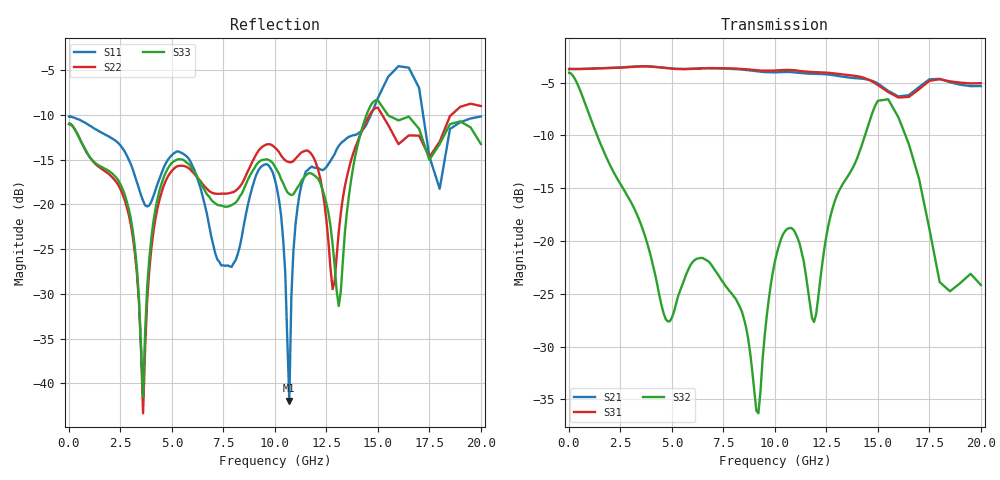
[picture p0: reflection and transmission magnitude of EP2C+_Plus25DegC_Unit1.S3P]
! Mini-Circuits
! S3P DATA File Format
! Type: 2 Way 0 degree Power Splitter
! Model: EP2C+
! Wafer / Lot / Date Code: BH102P002-02/03 / BH102P002-02/03-01EV / 1432
! AUTO PORT EXTENSION DONE: PORT<1>=128.60ps; PORT<2>=85.81ps; PORT<3>=85.38ps
! Network Analyzer: PNA-X N5242A - 423 4 ports;  Serial number: 71256
! PINOUT: SUMPORT=PORT1 , OUT1 PORT=PORT2 , OUT2 PORT=PORT3
! TEST CONDITIONS: INPUT POWER = -10 dBm @ Temperature = + 25 deg C
! S/N: Unit# 1
! Date: 09-Sep-2014
! All S Parameters are in dB deg format
# MHz S DB R 50
!Frequency  S11 dB  S11 DEG  S12 dB  S12 DEG  S13 dB  S13 DEG
!  S21 dB  S21 DEG  S22 dB  S22 DEG  S23 dB  S23 DEG
!  S31 dB  S31 DEG  S32 dB  S32 DEG  S33 dB  S33 DEG
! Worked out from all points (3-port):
!   169 points, 10 MHz to 20 GHz, reference 50 ohm
!   strongest paths, dB at 10 MHz, 3.4 GHz, 7.6 GHz, 11.8 GHz, 20 GHz:
!     S21: -3.7, -3.5, -3.7, -4.2, -5.3
!     S31: -3.7, -3.5, -3.6, -4.0, -5.1
!     S32: -4.1, -17.9, -24.3, -27.3, -24.2
!   lowest |S11| = -41.9 dB at 10.7 GHz (marker M1), VSWR 1.02, Z = 49.4 + j0.55 ohm
!   |S11| at or under -10 dB: start of sweep to 14.66 GHz; 17.2 GHz to end of sweep
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10  -10.18 179.9  -3.73 -0.7  -3.72 -0.3
    -3.73 -0.7  -11.02 178.5  -4.08 -0.7
    -3.72 -0.2  -4.07 -0.5  -11.01 177.9
3600  -19.59 50.8  -3.45 -142.0  -3.48 -143.8
      -3.45 -142.0  -43.33 -157.1  -18.98 -158.0
      -3.48 -143.7  -18.99 -158.0  -41.49 28.9
4500  -16.49 83.3  -3.57 -179.4  -3.59 178.4
      -3.57 -179.4  -18.63 86.4  -26.12 126.8
      -3.59 178.4  -26.13 126.8  -17.66 77.6
6700  -21.05 -8.6  -3.64 89.7  -3.65 86.7
      -3.65 89.7  -18.25 48.4  -21.85 -75.0
      -3.64 86.7  -21.85 -75.0  -18.88 51.9
10100  -18.23 14.3  -4.03 -62.3  -3.86 -66.8
       -4.03 -62.3  -13.88 81.3  -21.11 -57.0
       -3.86 -66.7  -21.13 -57.0  -16.14 68.3
10700  -41.94 135.9  -4.01 -90.7  -3.81 -95.9
       -4.00 -90.7  -15.29 92.8  -18.78 -93.2
       -3.81 -95.8  -18.78 -93.2  -18.84 72.9
11500  -16.33 164.6  -4.15 -129.1  -3.97 -135.1
       -4.15 -129.1  -13.98 98.7  -23.16 -130.8
       -3.96 -135.0  -23.16 -130.6  -16.77 75.9
13100  -13.47 -148.2  -4.39 151.7  -4.20 144.7
       -4.39 151.7  -23.09 170.9  -15.30 -100.2
       -4.19 144.8  -15.30 -100.0  -31.34 57.0
15500  -5.74 118.1  -5.79 28.1  -5.89 19.3
       -5.79 28.1  -11.13 35.1  -6.58 135.8
       -5.90 19.4  -6.59 135.9  -10.06 31.2
20000  -10.17 45.8  -5.34 154.9  -5.07 144.3
       -5.33 154.9  -9.01 74.0  -24.17 99.8
       -5.06 144.4  -24.17 100.0  -13.25 68.4
